VERSION 5.7 ;
  NOWIREEXTENSIONATPIN ON ;
  DIVIDERCHAR "/" ;
  BUSBITCHARS "[]" ;
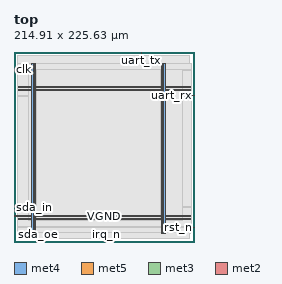
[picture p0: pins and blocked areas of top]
MACRO top
  CLASS BLOCK ;
  FOREIGN top ;
  ORIGIN 0.000 0.000 ;
  SIZE 214.910 BY 225.630 ;
  PIN VGND
    DIRECTION INOUT ;
    USE GROUND ;
    PORT
      LAYER met4 ;
        RECT 24.340 10.640 25.940 212.400 ;
    END
    PORT
      LAYER met4 ;
        RECT 177.940 10.640 179.540 212.400 ;
    END
    PORT
      LAYER met5 ;
        RECT 5.280 30.030 209.540 31.630 ;
    END
    PORT
      LAYER met5 ;
        RECT 5.280 183.210 209.540 184.810 ;
    END
  END VGND
  PIN VPWR
    DIRECTION INOUT ;
    USE POWER ;
    PORT
      LAYER met4 ;
        RECT 21.040 10.640 22.640 212.400 ;
    END
    PORT
      LAYER met4 ;
        RECT 174.640 10.640 176.240 212.400 ;
    END
    PORT
      LAYER met5 ;
        RECT 5.280 26.730 209.540 28.330 ;
    END
    PORT
      LAYER met5 ;
        RECT 5.280 179.910 209.540 181.510 ;
    END
  END VPWR
  PIN clk
    DIRECTION INPUT ;
    USE SIGNAL ;
    ANTENNAGATEAREA 0.852000 ;
    PORT
      LAYER met3 ;
        RECT 0.000 204.040 4.000 204.640 ;
    END
  END clk
  PIN irq_n
    DIRECTION OUTPUT ;
    USE SIGNAL ;
    ANTENNADIFFAREA 0.445500 ;
    PORT
      LAYER met2 ;
        RECT 109.570 0.000 109.850 4.000 ;
    END
  END irq_n
  PIN rst_n
    DIRECTION INPUT ;
    USE SIGNAL ;
    ANTENNAGATEAREA 0.196500 ;
    PORT
      LAYER met3 ;
        RECT 210.910 17.040 214.910 17.640 ;
    END
  END rst_n
  PIN scl_in
    DIRECTION INPUT ;
    USE SIGNAL ;
    ANTENNAGATEAREA 0.196500 ;
    PORT
      LAYER met3 ;
        RECT 0.000 30.640 4.000 31.240 ;
    END
  END scl_in
  PIN sda_in
    DIRECTION INPUT ;
    USE SIGNAL ;
    ANTENNAGATEAREA 0.196500 ;
    PORT
      LAYER met3 ;
        RECT 0.000 40.840 4.000 41.440 ;
    END
  END sda_in
  PIN sda_oe
    DIRECTION OUTPUT ;
    USE SIGNAL ;
    ANTENNADIFFAREA 0.445500 ;
    PORT
      LAYER met2 ;
        RECT 29.070 0.000 29.350 4.000 ;
    END
  END sda_oe
  PIN uart_rx
    DIRECTION INPUT ;
    USE SIGNAL ;
    ANTENNAGATEAREA 0.196500 ;
    PORT
      LAYER met3 ;
        RECT 210.910 173.440 214.910 174.040 ;
    END
  END uart_rx
  PIN uart_tx
    DIRECTION OUTPUT ;
    USE SIGNAL ;
    ANTENNADIFFAREA 0.795200 ;
    PORT
      LAYER met2 ;
        RECT 151.430 221.630 151.710 225.630 ;
    END
  END uart_tx
  OBS
      LAYER nwell ;
        RECT 5.330 10.795 209.490 212.245 ;
      LAYER li1 ;
        RECT 5.520 10.795 209.300 212.245 ;
      LAYER met1 ;
        RECT 4.210 10.640 209.300 212.400 ;
      LAYER met2 ;
        RECT 4.230 221.350 151.150 221.630 ;
        RECT 151.990 221.350 208.280 221.630 ;
        RECT 4.230 4.280 208.280 221.350 ;
        RECT 4.230 4.000 28.790 4.280 ;
        RECT 29.630 4.000 109.290 4.280 ;
        RECT 110.130 4.000 208.280 4.280 ;
      LAYER met3 ;
        RECT 3.990 205.040 210.910 212.325 ;
        RECT 4.400 203.640 210.910 205.040 ;
        RECT 3.990 174.440 210.910 203.640 ;
        RECT 3.990 173.040 210.510 174.440 ;
        RECT 3.990 41.840 210.910 173.040 ;
        RECT 4.400 40.440 210.910 41.840 ;
        RECT 3.990 31.640 210.910 40.440 ;
        RECT 4.400 30.240 210.910 31.640 ;
        RECT 3.990 18.040 210.910 30.240 ;
        RECT 3.990 16.640 210.510 18.040 ;
        RECT 3.990 10.715 210.910 16.640 ;
      LAYER met4 ;
        RECT 16.855 26.015 20.640 204.505 ;
        RECT 23.040 26.015 23.940 204.505 ;
        RECT 26.340 26.015 174.240 204.505 ;
        RECT 176.640 26.015 177.540 204.505 ;
        RECT 179.940 26.015 200.265 204.505 ;
  END
END top
END LIBRARY

